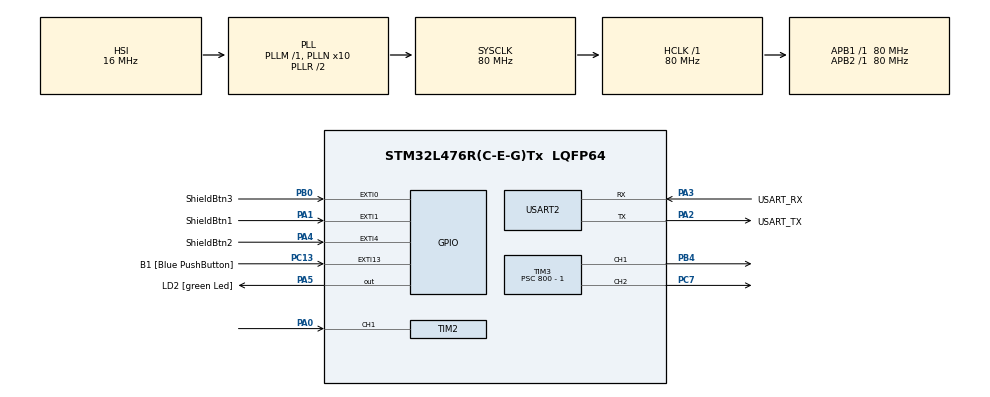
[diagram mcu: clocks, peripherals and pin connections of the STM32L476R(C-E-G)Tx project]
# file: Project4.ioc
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FREERTOS.Tasks01=defaultTask,0,128,StartDefaultTask,Default,NULL,Dynamic,NULL,NULL
FREERTOS.configUSE_NEWLIB_REENTRANT=1
Mcu.Family=STM32L4
Mcu.Name=STM32L476R(C-E-G)Tx
Mcu.Package=LQFP64
NVIC.EXTI0_IRQn=true\:5\:0\:false\:false\:true\:true\:true\:true\:true
NVIC.EXTI1_IRQn=true\:5\:0\:false\:false\:true\:true\:true\:true\:true
NVIC.EXTI4_IRQn=true\:5\:0\:false\:false\:true\:true\:true\:true\:true
NVIC.PriorityGroup=NVIC_PRIORITYGROUP_4
NVIC.TIM6_DAC_IRQn=true\:15\:0\:false\:false\:true\:false\:false\:true\:true
NVIC.TimeBase=TIM6_DAC_IRQn
NVIC.TimeBaseIP=TIM6
PA0.Signal=S_TIM2_CH1
PA1.GPIO_Label=ShieldBtn1
PA1.GPIO_ModeDefaultEXTI=GPIO_MODE_IT_FALLING
PA1.Signal=GPXTI1
PA13\ (JTMS-SWDIO).GPIO_Label=TMS
PA13\ (JTMS-SWDIO).Mode=Serial_Wire
PA13\ (JTMS-SWDIO).Signal=SYS_JTMS-SWDIO
PA14\ (JTCK-SWCLK).GPIO_Label=TCK
PA14\ (JTCK-SWCLK).Mode=Serial_Wire
PA14\ (JTCK-SWCLK).Signal=SYS_JTCK-SWCLK
PA2.GPIO_Label=USART_TX
PA2.GPIO_Mode=GPIO_MODE_AF_PP
PA2.GPIO_PuPd=GPIO_NOPULL
PA2.GPIO_Speed=GPIO_SPEED_FREQ_VERY_HIGH
PA2.Mode=Asynchronous
PA2.Signal=USART2_TX
PA3.GPIO_Label=USART_RX
PA3.GPIO_Mode=GPIO_MODE_AF_PP
PA3.GPIO_PuPd=GPIO_NOPULL
PA3.GPIO_Speed=GPIO_SPEED_FREQ_VERY_HIGH
PA3.Mode=Asynchronous
PA3.Signal=USART2_RX
PA4.GPIO_Label=ShieldBtn2
PA4.GPIO_ModeDefaultEXTI=GPIO_MODE_IT_FALLING
PA4.Signal=GPXTI4
PA5.GPIO_Label=LD2 [green Led]
PA5.GPIO_ModeDefaultOutputPP=GPIO_MODE_OUTPUT_PP
PA5.GPIO_PuPd=GPIO_NOPULL
PA5.GPIO_Speed=GPIO_SPEED_FREQ_LOW
PA5.Signal=GPIO_Output
PB0.GPIO_Label=ShieldBtn3
PB0.GPIO_ModeDefaultEXTI=GPIO_MODE_IT_FALLING
PB0.Signal=GPXTI0
PB3\ (JTDO-TRACESWO).GPIO_Label=SWO
PB3\ (JTDO-TRACESWO).Signal=SYS_JTDO-SWO
PB4\ (NJTRST).Signal=S_TIM3_CH1
PC13.GPIO_Label=B1 [Blue PushButton]
PC13.GPIO_ModeDefaultEXTI=GPIO_MODE_IT_FALLING
PC13.GPIO_PuPd=GPIO_NOPULL
PC13.Signal=GPXTI13
PC14-OSC32_IN\ (PC14).Mode=LSE-External-Oscillator
PC14-OSC32_IN\ (PC14).Signal=RCC_OSC32_IN
PC15-OSC32_OUT\ (PC15).Mode=LSE-External-Oscillator
PC15-OSC32_OUT\ (PC15).Signal=RCC_OSC32_OUT
PC7.Signal=S_TIM3_CH2
PH0-OSC_IN\ (PH0).Signal=RCC_OSC_IN
PH1-OSC_OUT\ (PH1).Signal=RCC_OSC_OUT
ProjectManager.HeapSize=0x200
ProjectManager.StackSize=0x400
ProjectManager.TargetToolchain=STM32CubeIDE
RCC.ADCFreq_Value=64000000
RCC.AHBFreq_Value=80000000
RCC.APB1Freq_Value=80000000
RCC.APB1TimFreq_Value=80000000
RCC.APB2Freq_Value=80000000
RCC.APB2TimFreq_Value=80000000
RCC.CortexFreq_Value=80000000
RCC.HCLKFreq_Value=80000000
RCC.HSE_VALUE=8000000
RCC.HSI_VALUE=16000000
RCC.MSI_VALUE=4000000
RCC.PLLN=10
RCC.PLLSAI1Q=RCC_PLLQ_DIV4
RCC.PLLSourceVirtual=RCC_PLLSOURCE_HSI
RCC.PREFETCH_ENABLE=1
RCC.SYSCLKFreq_VALUE=80000000
RCC.SYSCLKSource=RCC_SYSCLKSOURCE_PLLCLK
RCC.USBFreq_Value=32000000
RCC.VCOOutputFreq_Value=160000000
SH.S_TIM2_CH1.0=TIM2_CH1,Input_Capture1_from_TI1
SH.S_TIM3_CH1.0=TIM3_CH1,PWM Generation1 CH1
SH.S_TIM3_CH2.0=TIM3_CH2,PWM Generation2 CH2
TIM2.Channel-Input_Capture1_from_TI1=TIM_CHANNEL_1
TIM3.Channel-PWM\ Generation1\ CH1=TIM_CHANNEL_1
TIM3.Channel-PWM\ Generation2\ CH2=TIM_CHANNEL_2
TIM3.Period=2000 - 1
TIM3.Prescaler=800 - 1
USART2.VirtualMode-Asynchronous=VM_ASYNC
VP_FREERTOS_VS_CMSIS_V1.Mode=CMSIS_V1
VP_RNG_VS_RNG.Mode=RNG_Activate
VP_SYS_VS_tim6.Mode=TIM6
VP_TIM2_VS_ClockSourceINT.Mode=Internal
VP_TIM3_VS_ClockSourceINT.Mode=Internal
board=NUCLEO-L476RG

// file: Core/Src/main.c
/* USER CODE BEGIN Header */
/**
  ******************************************************************************
  * @file           : main.c
  * @brief          : Main program body
  ******************************************************************************
  * @attention
  *
  * Copyright (c) 2022 STMicroelectronics.
  * All rights reserved.
  *
  * This software is licensed under terms that can be found in the LICENSE file
  * in the root directory of this software component.
  * If no LICENSE file comes with this software, it is provided AS-IS.
  *
  ******************************************************************************
  */
/* USER CODE END Header */
#include "main.h"
#include "cmsis_os.h"

/* USER CODE BEGIN Includes */
#include "game_control.h"
/* USER CODE END Includes */

RNG_HandleTypeDef hrng;

TIM_HandleTypeDef htim2;
TIM_HandleTypeDef htim3;

UART_HandleTypeDef huart2;

osThreadId defaultTaskHandle;

void SystemClock_Config(void);
static void MX_GPIO_Init(void);
static void MX_USART2_UART_Init(void);
static void MX_RNG_Init(void);
static void MX_TIM3_Init(void);
static void MX_TIM2_Init(void);
void StartDefaultTask(void const * argument);

int main(void)
{

  /* MCU Configuration--------------------------------------------------------*/

  /* Reset of all peripherals, Initializes the Flash interface and the Systick. */
  HAL_Init();

  /* Configure the system clock */
  SystemClock_Config();

  /* Initialize all configured peripherals */
  MX_GPIO_Init();
  MX_USART2_UART_Init();
  MX_RNG_Init();
  MX_TIM3_Init();
  MX_TIM2_Init();
  /* USER CODE BEGIN 2 */
  HAL_TIM_PWM_Start(&htim3, TIM_CHANNEL_1);
  HAL_TIM_PWM_Start(&htim3, TIM_CHANNEL_2);
  /* USER CODE END 2 */

  /* USER CODE BEGIN RTOS_SEMAPHORES */
  /* add semaphores, ... */
  xTaskHandle game_handler;
  xTaskHandle display_handler;
  xTaskHandle score_handler;
  /* USER CODE END RTOS_SEMAPHORES */

  /* Create the thread(s) */
  /* definition and creation of defaultTask */

  /* USER CODE BEGIN RTOS_THREADS */
  xTaskCreate(game_task, "Game", 128, NULL, 3, &game_handler);
  xTaskCreate(display_task, "Display", 128, NULL, 3, &display_handler);
  xTaskCreate(score_task, "Score", 128, NULL, 3, &score_handler);
  /* USER CODE END RTOS_THREADS */

  /* Start scheduler */
  osKernelStart();

  /* We should never get here as control is now taken by the scheduler */
  /* Infinite loop */
  while (1)
  {

  }
}

void SystemClock_Config(void)
{
  RCC_OscInitTypeDef RCC_OscInitStruct = {0};
  RCC_ClkInitTypeDef RCC_ClkInitStruct = {0};

  /** Configure the main internal regulator output voltage
  */
  if (HAL_PWREx_ControlVoltageScaling(PWR_REGULATOR_VOLTAGE_SCALE1) != HAL_OK)
  {
    Error_Handler();
  }

  /** Initializes the RCC Oscillators according to the specified parameters
  * in the RCC_OscInitTypeDef structure.
  */
  RCC_OscInitStruct.OscillatorType = RCC_OSCILLATORTYPE_HSI;
  RCC_OscInitStruct.HSIState = RCC_HSI_ON;
  RCC_OscInitStruct.HSICalibrationValue = RCC_HSICALIBRATION_DEFAULT;
  RCC_OscInitStruct.PLL.PLLState = RCC_PLL_ON;
  RCC_OscInitStruct.PLL.PLLSource = RCC_PLLSOURCE_HSI;
  RCC_OscInitStruct.PLL.PLLM = 1;
  RCC_OscInitStruct.PLL.PLLN = 10;
  RCC_OscInitStruct.PLL.PLLP = RCC_PLLP_DIV7;
  RCC_OscInitStruct.PLL.PLLQ = RCC_PLLQ_DIV2;
  RCC_OscInitStruct.PLL.PLLR = RCC_PLLR_DIV2;
  if (HAL_RCC_OscConfig(&RCC_OscInitStruct) != HAL_OK)
  {
    Error_Handler();
  }

  /** Initializes the CPU, AHB and APB buses clocks
  */
  RCC_ClkInitStruct.ClockType = RCC_CLOCKTYPE_HCLK|RCC_CLOCKTYPE_SYSCLK
                              |RCC_CLOCKTYPE_PCLK1|RCC_CLOCKTYPE_PCLK2;
  RCC_ClkInitStruct.SYSCLKSource = RCC_SYSCLKSOURCE_PLLCLK;
  RCC_ClkInitStruct.AHBCLKDivider = RCC_SYSCLK_DIV1;
  RCC_ClkInitStruct.APB1CLKDivider = RCC_HCLK_DIV1;
  RCC_ClkInitStruct.APB2CLKDivider = RCC_HCLK_DIV1;

  if (HAL_RCC_ClockConfig(&RCC_ClkInitStruct, FLASH_LATENCY_4) != HAL_OK)
  {
    Error_Handler();
  }
}

static void MX_RNG_Init(void)
{

  hrng.Instance = RNG;
  if (HAL_RNG_Init(&hrng) != HAL_OK)
  {
    Error_Handler();
  }

}

static void MX_TIM2_Init(void)
{

  TIM_ClockConfigTypeDef sClockSourceConfig = {0};
  TIM_MasterConfigTypeDef sMasterConfig = {0};
  TIM_IC_InitTypeDef sConfigIC = {0};

  htim2.Instance = TIM2;
  htim2.Init.Prescaler = 80 - 1;
  htim2.Init.CounterMode = TIM_COUNTERMODE_UP;
  htim2.Init.Period = 4294967295;
  htim2.Init.ClockDivision = TIM_CLOCKDIVISION_DIV1;
  htim2.Init.AutoReloadPreload = TIM_AUTORELOAD_PRELOAD_DISABLE;
  if (HAL_TIM_Base_Init(&htim2) != HAL_OK)
  {
    Error_Handler();
  }
  sClockSourceConfig.ClockSource = TIM_CLOCKSOURCE_INTERNAL;
  if (HAL_TIM_ConfigClockSource(&htim2, &sClockSourceConfig) != HAL_OK)
  {
    Error_Handler();
  }
  if (HAL_TIM_IC_Init(&htim2) != HAL_OK)
  {
    Error_Handler();
  }
  sMasterConfig.MasterOutputTrigger = TIM_TRGO_RESET;
  sMasterConfig.MasterSlaveMode = TIM_MASTERSLAVEMODE_DISABLE;
  if (HAL_TIMEx_MasterConfigSynchronization(&htim2, &sMasterConfig) != HAL_OK)
  {
    Error_Handler();
  }
  sConfigIC.ICPolarity = TIM_INPUTCHANNELPOLARITY_RISING;
  sConfigIC.ICSelection = TIM_ICSELECTION_DIRECTTI;
  sConfigIC.ICPrescaler = TIM_ICPSC_DIV1;
  sConfigIC.ICFilter = 0;
  if (HAL_TIM_IC_ConfigChannel(&htim2, &sConfigIC, TIM_CHANNEL_1) != HAL_OK)
  {
    Error_Handler();
  }

}

static void MX_TIM3_Init(void)
{

  TIM_ClockConfigTypeDef sClockSourceConfig = {0};
  TIM_MasterConfigTypeDef sMasterConfig = {0};
  TIM_OC_InitTypeDef sConfigOC = {0};

  htim3.Instance = TIM3;
  htim3.Init.Prescaler = 800 - 1;
  htim3.Init.CounterMode = TIM_COUNTERMODE_UP;
  htim3.Init.Period = 2000 - 1;
  htim3.Init.ClockDivision = TIM_CLOCKDIVISION_DIV1;
  htim3.Init.AutoReloadPreload = TIM_AUTORELOAD_PRELOAD_DISABLE;
  if (HAL_TIM_Base_Init(&htim3) != HAL_OK)
  {
    Error_Handler();
  }
  sClockSourceConfig.ClockSource = TIM_CLOCKSOURCE_INTERNAL;
  if (HAL_TIM_ConfigClockSource(&htim3, &sClockSourceConfig) != HAL_OK)
  {
    Error_Handler();
  }
  if (HAL_TIM_PWM_Init(&htim3) != HAL_OK)
  {
    Error_Handler();
  }
  sMasterConfig.MasterOutputTrigger = TIM_TRGO_RESET;
  sMasterConfig.MasterSlaveMode = TIM_MASTERSLAVEMODE_DISABLE;
  if (HAL_TIMEx_MasterConfigSynchronization(&htim3, &sMasterConfig) != HAL_OK)
  {
    Error_Handler();
  }
  sConfigOC.OCMode = TIM_OCMODE_PWM1;
  sConfigOC.Pulse = 0;
  sConfigOC.OCPolarity = TIM_OCPOLARITY_HIGH;
  sConfigOC.OCFastMode = TIM_OCFAST_DISABLE;
  if (HAL_TIM_PWM_ConfigChannel(&htim3, &sConfigOC, TIM_CHANNEL_1) != HAL_OK)
  {
    Error_Handler();
  }
  if (HAL_TIM_PWM_ConfigChannel(&htim3, &sConfigOC, TIM_CHANNEL_2) != HAL_OK)
  {
    Error_Handler();
  }
  HAL_TIM_MspPostInit(&htim3);

}

static void MX_USART2_UART_Init(void)
{

  huart2.Instance = USART2;
  huart2.Init.BaudRate = 115200;
  huart2.Init.WordLength = UART_WORDLENGTH_8B;
  huart2.Init.StopBits = UART_STOPBITS_1;
  huart2.Init.Parity = UART_PARITY_NONE;
  huart2.Init.Mode = UART_MODE_TX_RX;
  huart2.Init.HwFlowCtl = UART_HWCONTROL_NONE;
  huart2.Init.OverSampling = UART_OVERSAMPLING_16;
  huart2.Init.OneBitSampling = UART_ONE_BIT_SAMPLE_DISABLE;
  huart2.AdvancedInit.AdvFeatureInit = UART_ADVFEATURE_NO_INIT;
  if (HAL_UART_Init(&huart2) != HAL_OK)
  {
    Error_Handler();
  }

}

static void MX_GPIO_Init(void)
{
	GPIO_InitTypeDef GPIO_InitStruct = {0};

	/* GPIO Ports Clock Enable */
	__HAL_RCC_GPIOC_CLK_ENABLE();
	__HAL_RCC_GPIOH_CLK_ENABLE();
	__HAL_RCC_GPIOA_CLK_ENABLE();
	__HAL_RCC_GPIOB_CLK_ENABLE();

	/*Configure GPIO pin Output Level */
	HAL_GPIO_WritePin(LD2_GPIO_Port, LD2_Pin, GPIO_PIN_RESET);

	/*Configure GPIO pin : B1_Pin */
	GPIO_InitStruct.Pin = B1_Pin;
	GPIO_InitStruct.Mode = GPIO_MODE_IT_FALLING;
	GPIO_InitStruct.Pull = GPIO_NOPULL;
	HAL_GPIO_Init(B1_GPIO_Port, &GPIO_InitStruct);

	/*Configure GPIO pins : ShieldBtn1_Pin ShieldBtn2_Pin */
	GPIO_InitStruct.Pin = ShieldBtn1_Pin|ShieldBtn2_Pin;
	GPIO_InitStruct.Mode = GPIO_MODE_IT_FALLING;
	GPIO_InitStruct.Pull = GPIO_PULLUP;
	HAL_GPIO_Init(GPIOA, &GPIO_InitStruct);

	/*Configure GPIO pin : LD2_Pin */
	GPIO_InitStruct.Pin = LD2_Pin;
	GPIO_InitStruct.Mode = GPIO_MODE_OUTPUT_PP;
	GPIO_InitStruct.Pull = GPIO_NOPULL;
	GPIO_InitStruct.Speed = GPIO_SPEED_FREQ_LOW;
	HAL_GPIO_Init(LD2_GPIO_Port, &GPIO_InitStruct);

	/*Configure GPIO pin : ShieldBtn3_Pin */
	GPIO_InitStruct.Pin = ShieldBtn3_Pin;
	GPIO_InitStruct.Mode = GPIO_MODE_IT_FALLING;
	GPIO_InitStruct.Pull = GPIO_PULLUP;
	HAL_GPIO_Init(ShieldBtn3_GPIO_Port, &GPIO_InitStruct);

	/*Configure GPIO pins : SHLD_A5_Pin SHLD_A4_Pin */
	GPIO_InitStruct.Pin = SHLD_A5_Pin|SHLD_A4_Pin;
	GPIO_InitStruct.Mode = GPIO_MODE_ANALOG;
	GPIO_InitStruct.Pull = GPIO_NOPULL;
	HAL_GPIO_Init(GPIOC, &GPIO_InitStruct);

	/*Configure GPIO pins : SHLD_A0_Pin SHLD_D2_Pin */
	GPIO_InitStruct.Pin = SHLD_A0_Pin|SHLD_D2_Pin;
	GPIO_InitStruct.Mode = GPIO_MODE_INPUT;
	GPIO_InitStruct.Pull = GPIO_NOPULL;
	HAL_GPIO_Init(GPIOA, &GPIO_InitStruct);

	/*Configure GPIO pins : SHLD_D13_Pin SHLD_D12_Pin SHLD_D11_Pin SHLD_D7_SEG7_Clock_Pin */
	GPIO_InitStruct.Pin = SHLD_D13_Pin|SHLD_D12_Pin|SHLD_D11_Pin|SHLD_D7_SEG7_Clock_Pin;
	GPIO_InitStruct.Mode = GPIO_MODE_OUTPUT_PP;
	GPIO_InitStruct.Pull = GPIO_NOPULL;
	GPIO_InitStruct.Speed = GPIO_SPEED_FREQ_LOW;
	HAL_GPIO_Init(GPIOA, &GPIO_InitStruct);

	/*Configure GPIO pins : SHLD_D6_Pin SHLD_D5_Pin */
	GPIO_InitStruct.Pin = SHLD_D6_Pin|SHLD_D5_Pin;
	GPIO_InitStruct.Mode = GPIO_MODE_INPUT;
	GPIO_InitStruct.Pull = GPIO_NOPULL;
	HAL_GPIO_Init(GPIOB, &GPIO_InitStruct);

	/*Configure GPIO pin : SHLD_D9_Pin */
	GPIO_InitStruct.Pin = SHLD_D9_Pin;
	GPIO_InitStruct.Mode = GPIO_MODE_INPUT;
	GPIO_InitStruct.Pull = GPIO_NOPULL;
	HAL_GPIO_Init(SHLD_D9_GPIO_Port, &GPIO_InitStruct);

	/*Configure GPIO pin : SHLD_D8_SEG7_Data_Pin */
	GPIO_InitStruct.Pin = SHLD_D8_SEG7_Data_Pin;
	GPIO_InitStruct.Mode = GPIO_MODE_OUTPUT_PP;
	GPIO_InitStruct.Pull = GPIO_NOPULL;
	GPIO_InitStruct.Speed = GPIO_SPEED_FREQ_MEDIUM;
	HAL_GPIO_Init(SHLD_D8_SEG7_Data_GPIO_Port, &GPIO_InitStruct);

	/*Configure GPIO pin : SHLD_D3_Pin */
	GPIO_InitStruct.Pin = SHLD_D3_Pin;
	GPIO_InitStruct.Mode = GPIO_MODE_OUTPUT_OD;
	GPIO_InitStruct.Pull = GPIO_NOPULL;
	GPIO_InitStruct.Speed = GPIO_SPEED_FREQ_HIGH;
	HAL_GPIO_Init(SHLD_D3_GPIO_Port, &GPIO_InitStruct);

	/*Configure GPIO pin : SHLD_D4_SEG7_Latch_Pin */
	GPIO_InitStruct.Pin = SHLD_D4_SEG7_Latch_Pin;
	GPIO_InitStruct.Mode = GPIO_MODE_OUTPUT_PP;
	GPIO_InitStruct.Pull = GPIO_NOPULL;
	GPIO_InitStruct.Speed = GPIO_SPEED_FREQ_HIGH;
	HAL_GPIO_Init(SHLD_D4_SEG7_Latch_GPIO_Port, &GPIO_InitStruct);

	/*Configure GPIO pin : SHLD_D10_Pin */
	GPIO_InitStruct.Pin = SHLD_D10_Pin;
	GPIO_InitStruct.Mode = GPIO_MODE_OUTPUT_PP;
	GPIO_InitStruct.Pull = GPIO_NOPULL;
	GPIO_InitStruct.Speed = GPIO_SPEED_FREQ_LOW;
	HAL_GPIO_Init(SHLD_D10_GPIO_Port, &GPIO_InitStruct);

	/*Configure GPIO pins : SHLD_D15_Pin SHLD_D14_Pin */
	GPIO_InitStruct.Pin = SHLD_D15_Pin|SHLD_D14_Pin;
	GPIO_InitStruct.Mode = GPIO_MODE_AF_OD;
	GPIO_InitStruct.Pull = GPIO_NOPULL;
	GPIO_InitStruct.Speed = GPIO_SPEED_FREQ_VERY_HIGH;
	GPIO_InitStruct.Alternate = GPIO_AF4_I2C1;
	HAL_GPIO_Init(GPIOB, &GPIO_InitStruct);

	/* EXTI interrupt init*/
	HAL_NVIC_SetPriority(EXTI0_IRQn, 5, 0);
	HAL_NVIC_EnableIRQ(EXTI0_IRQn);

	HAL_NVIC_SetPriority(EXTI1_IRQn, 5, 0);
	HAL_NVIC_EnableIRQ(EXTI1_IRQn);

	HAL_NVIC_SetPriority(EXTI4_IRQn, 5, 0);
	HAL_NVIC_EnableIRQ(EXTI4_IRQn);

}

void StartDefaultTask(void const * argument)
{
  for(;;)
  {
    osDelay(1);
  }
}

void HAL_TIM_PeriodElapsedCallback(TIM_HandleTypeDef *htim)
{
  if (htim->Instance == TIM6) {
    HAL_IncTick();
  }
}

void Error_Handler(void)
{
  __disable_irq();
  while (1)
  {
  }
}
